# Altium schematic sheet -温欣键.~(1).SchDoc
size A4

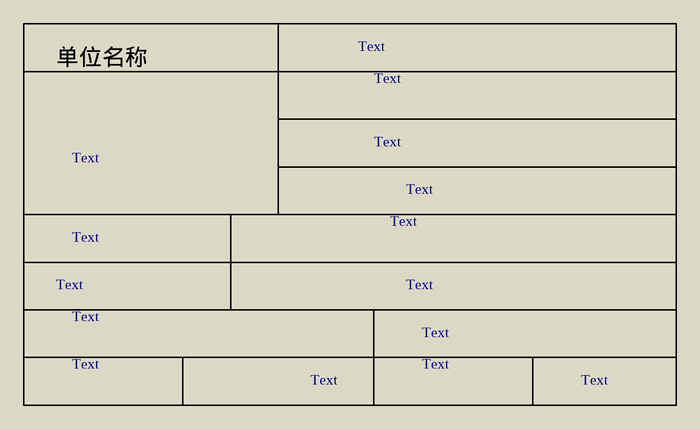
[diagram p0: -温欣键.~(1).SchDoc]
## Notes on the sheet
- 单位名称
- Text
